VERSION 5.7 ;
  NOWIREEXTENSIONATPIN ON ;
  DIVIDERCHAR "/" ;
  BUSBITCHARS "[]" ;
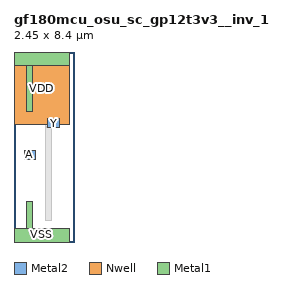
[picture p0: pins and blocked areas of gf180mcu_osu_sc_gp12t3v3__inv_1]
MACRO gf180mcu_osu_sc_gp12t3v3__inv_1
  CLASS BLOCK ;
  FOREIGN gf180mcu_osu_sc_gp12t3v3__inv_1 ;
  ORIGIN 0.000 0.000 ;
  SIZE 2.450 BY 8.400 ;
  PIN A
    ANTENNAGATEAREA 0.765000 ;
    PORT
      LAYER Metal2 ;
        RECT 0.450 3.650 0.950 4.050 ;
    END
  END A
  PIN Y
    ANTENNADIFFAREA 1.275000 ;
    PORT
      LAYER Metal2 ;
        RECT 1.500 5.050 2.000 5.450 ;
    END
  END Y
  PIN VDD
    ANTENNADIFFAREA 1.187500 ;
    PORT
      LAYER Nwell ;
        RECT 0.000 5.200 2.450 8.400 ;
      LAYER Metal1 ;
        RECT 0.000 7.800 2.450 8.400 ;
        RECT 0.550 5.750 0.800 7.800 ;
    END
  END VDD
  PIN VSS
    ANTENNADIFFAREA 0.762500 ;
    PORT
      LAYER Metal1 ;
        RECT 0.550 0.600 0.800 1.800 ;
        RECT 0.000 0.000 2.450 0.600 ;
    END
  END VSS
  OBS
      LAYER Metal1 ;
        RECT 1.400 5.450 1.650 7.450 ;
        RECT 1.400 5.400 1.850 5.450 ;
        RECT 1.400 5.100 2.000 5.400 ;
        RECT 1.400 5.050 1.850 5.100 ;
        RECT 0.450 3.700 0.950 4.000 ;
        RECT 1.400 0.950 1.650 5.050 ;
  END
END gf180mcu_osu_sc_gp12t3v3__inv_1
END LIBRARY

